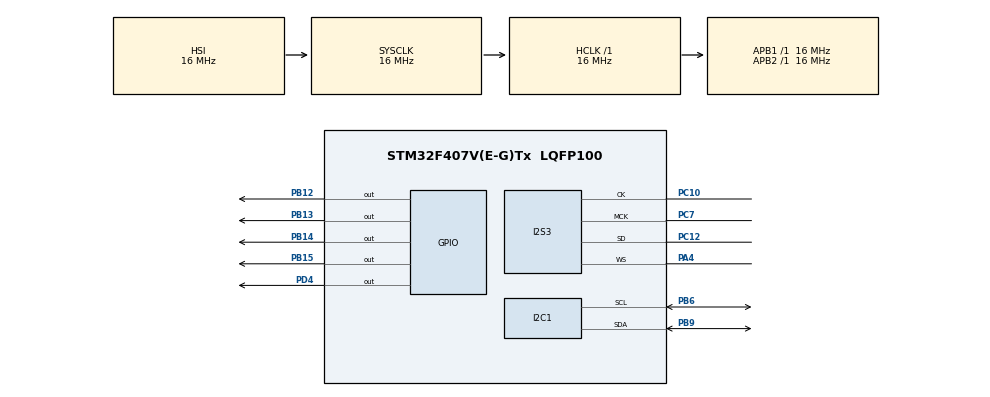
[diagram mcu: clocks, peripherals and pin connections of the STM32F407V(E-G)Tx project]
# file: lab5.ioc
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Dma.Request0=SPI3_TX
Dma.SPI3_TX.0.Direction=DMA_MEMORY_TO_PERIPH
Dma.SPI3_TX.0.FIFOMode=DMA_FIFOMODE_ENABLE
Dma.SPI3_TX.0.FIFOThreshold=DMA_FIFO_THRESHOLD_FULL
Dma.SPI3_TX.0.Instance=DMA1_Stream5
Dma.SPI3_TX.0.MemBurst=DMA_MBURST_SINGLE
Dma.SPI3_TX.0.MemDataAlignment=DMA_MDATAALIGN_HALFWORD
Dma.SPI3_TX.0.MemInc=DMA_MINC_ENABLE
Dma.SPI3_TX.0.Mode=DMA_CIRCULAR
Dma.SPI3_TX.0.PeriphBurst=DMA_PBURST_SINGLE
Dma.SPI3_TX.0.PeriphDataAlignment=DMA_PDATAALIGN_HALFWORD
Dma.SPI3_TX.0.PeriphInc=DMA_PINC_DISABLE
Dma.SPI3_TX.0.Priority=DMA_PRIORITY_LOW
I2S3.AudioFreq=I2S_AUDIOFREQ_48K
I2S3.ErrorAudioFreq=-2.34 %
I2S3.FullDuplexMode=I2S_FULLDUPLEXMODE_DISABLE
I2S3.Instance=SPI$Index
I2S3.RealAudioFreq=46.875 KHz
I2S3.VirtualMode=I2S_MODE_MASTER
Mcu.Family=STM32F4
Mcu.Name=STM32F407V(E-G)Tx
Mcu.Package=LQFP100
NVIC.DMA1_Stream5_IRQn=true\:0\:0\:false\:false\:true\:false\:true\:true
NVIC.PriorityGroup=NVIC_PRIORITYGROUP_4
PA4.Mode=Half_Duplex_Master
PA4.Signal=I2S3_WS
PB12.Signal=GPIO_Output
PB13.Signal=GPIO_Output
PB14.Signal=GPIO_Output
PB15.Signal=GPIO_Output
PB6.Mode=I2C
PB6.Signal=I2C1_SCL
PB9.Mode=I2C
PB9.Signal=I2C1_SDA
PC10.Mode=Half_Duplex_Master
PC10.Signal=I2S3_CK
PC12.Mode=Half_Duplex_Master
PC12.Signal=I2S3_SD
PC7.Mode=Master_Clock_Activated
PC7.Signal=I2S3_MCK
PD4.Signal=GPIO_Output
ProjectManager.HeapSize=0x200
ProjectManager.StackSize=0x400
ProjectManager.TargetToolchain=STM32CubeIDE
RCC.AHBFreq_Value=16000000
RCC.APB1Freq_Value=16000000
RCC.APB2Freq_Value=16000000
RCC.CortexFreq_Value=16000000
RCC.HSE_VALUE=25000000
RCC.HSI_VALUE=16000000
RCC.LSE_VALUE=32768
RCC.SYSCLKFreq_VALUE=16000000
RCC.VCOOutputFreq_Value=192000000
board=custom

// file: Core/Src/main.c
/* USER CODE BEGIN Header */
/**
  ******************************************************************************
  * @file           : main.c
  * @brief          : Main program body
  ******************************************************************************
  * @attention
  *
  * Copyright (c) 2024 STMicroelectronics.
  * All rights reserved.
  *
  * This software is licensed under terms that can be found in the LICENSE file
  * in the root directory of this software component.
  * If no LICENSE file comes with this software, it is provided AS-IS.
  *
  ******************************************************************************
  */
/* USER CODE END Header */
#include "main.h"

/* USER CODE BEGIN PTD */

typedef enum
{
	C4,
	C5,
	D5,
	E5,
	F5,
	G5,
	A5,
	B5,
	C6,
	D6,
	E6,
	F6,
	G6,
	A6,
	B6,
	C7,
	MAX_VALUE
} soundToneType;

/* USER CODE END PTD */

/* USER CODE BEGIN PD */

#define CS43L22_I2C_ADDRESS		0x94
#define I2C_TIMEOUT				10

/* USER CODE END PD */

I2C_HandleTypeDef hi2c1;

I2S_HandleTypeDef hi2s3;
DMA_HandleTypeDef hdma_spi3_tx;

/* USER CODE BEGIN PV */

int16_t dataI2S[100] = {0};

/* USER CODE END PV */

void SystemClock_Config(void);
static void MX_GPIO_Init(void);
static void MX_DMA_Init(void);
static void MX_I2C1_Init(void);
static void MX_I2S3_Init(void);

/* USER CODE BEGIN 0 */
void CS43L22_Init(void)
{
	// Enable chip
	HAL_GPIO_WritePin(GPIOD, GPIO_PIN_4, GPIO_PIN_SET);

	//
	// Initialization
	//
	uint8_t TxBuffer[2];

	TxBuffer[0] = 0x0D;
	TxBuffer[1] = 0x01;
	HAL_I2C_Master_Transmit(&hi2c1, CS43L22_I2C_ADDRESS, (uint8_t*) &TxBuffer, 2, I2C_TIMEOUT);

	TxBuffer[0] = 0x00;
	TxBuffer[1] = 0x99;
	HAL_I2C_Master_Transmit(&hi2c1, CS43L22_I2C_ADDRESS, (uint8_t*) &TxBuffer, 2, I2C_TIMEOUT);

	TxBuffer[0] = 0x47;
	TxBuffer[1] = 0x80;
	HAL_I2C_Master_Transmit(&hi2c1, CS43L22_I2C_ADDRESS, (uint8_t*) &TxBuffer, 2, I2C_TIMEOUT);

	TxBuffer[0] = 0x32;
	TxBuffer[1] = 0xFF;
	HAL_I2C_Master_Transmit(&hi2c1, CS43L22_I2C_ADDRESS, (uint8_t*) &TxBuffer, 2, I2C_TIMEOUT);

	TxBuffer[0] = 0x32;
	TxBuffer[1] = 0x7F;
	HAL_I2C_Master_Transmit(&hi2c1, CS43L22_I2C_ADDRESS, (uint8_t*) &TxBuffer, 2, I2C_TIMEOUT);

	TxBuffer[0] = 0x00;
	TxBuffer[1] = 0x00;
	HAL_I2C_Master_Transmit(&hi2c1, CS43L22_I2C_ADDRESS, (uint8_t*) &TxBuffer, 2, I2C_TIMEOUT);

	TxBuffer[0] = 0x04;
	TxBuffer[1] = 0xAF;
	HAL_I2C_Master_Transmit(&hi2c1, CS43L22_I2C_ADDRESS, (uint8_t*) &TxBuffer, 2, I2C_TIMEOUT);

	TxBuffer[0] = 0x0D;
	TxBuffer[1] = 0x70;
	HAL_I2C_Master_Transmit(&hi2c1, CS43L22_I2C_ADDRESS, (uint8_t*) &TxBuffer, 2, I2C_TIMEOUT);

	TxBuffer[0] = 0x05;
	TxBuffer[1] = 0x81;
	HAL_I2C_Master_Transmit(&hi2c1, CS43L22_I2C_ADDRESS, (uint8_t*) &TxBuffer, 2, I2C_TIMEOUT);

	TxBuffer[0] = 0x06;
	TxBuffer[1] = 0x07;
	HAL_I2C_Master_Transmit(&hi2c1, CS43L22_I2C_ADDRESS, (uint8_t*) &TxBuffer, 2, I2C_TIMEOUT);

	TxBuffer[0] = 0x0A;
	TxBuffer[1] = 0x00;
	HAL_I2C_Master_Transmit(&hi2c1, CS43L22_I2C_ADDRESS, (uint8_t*) &TxBuffer, 2, I2C_TIMEOUT);

	TxBuffer[0] = 0x27;
	TxBuffer[1] = 0x00;
	HAL_I2C_Master_Transmit(&hi2c1, CS43L22_I2C_ADDRESS, (uint8_t*) &TxBuffer, 2, I2C_TIMEOUT);

	TxBuffer[0] = 0x1A;
	TxBuffer[1] = 0x0A;
	HAL_I2C_Master_Transmit(&hi2c1, CS43L22_I2C_ADDRESS, (uint8_t*) &TxBuffer, 2, I2C_TIMEOUT);

	TxBuffer[0] = 0x1B;
	TxBuffer[1] = 0x0A;
	HAL_I2C_Master_Transmit(&hi2c1, CS43L22_I2C_ADDRESS, (uint8_t*) &TxBuffer, 2, I2C_TIMEOUT);

	TxBuffer[0] = 0x1F;
	TxBuffer[1] = 0x0F;
	HAL_I2C_Master_Transmit(&hi2c1, CS43L22_I2C_ADDRESS, (uint8_t*) &TxBuffer, 2, I2C_TIMEOUT);

	TxBuffer[0] = 0x02;
	TxBuffer[1] = 0x9E;
	HAL_I2C_Master_Transmit(&hi2c1, CS43L22_I2C_ADDRESS, (uint8_t*) &TxBuffer, 2, I2C_TIMEOUT);
}

void CS43L22_Beep(soundToneType pitch, uint32_t duration_ms)
{
	uint8_t TxBuffer[2];

	// Set volume and off time
	TxBuffer[0] = 0x1D;		// Register address
	TxBuffer[1] = 0x00;		// Value (volume and off time)
	HAL_I2C_Master_Transmit(&hi2c1, CS43L22_I2C_ADDRESS, (uint8_t*) &TxBuffer, 2, I2C_TIMEOUT);

	// Set sound frequency
	TxBuffer[0] = 0x1C;		// Register address
	switch (pitch)
	{
		case C4:
			TxBuffer[1] = 0x00;		// Value (frequency and on time)
			break;
		case C5:
			TxBuffer[1] = 0x10;
		case D5:
			TxBuffer[1] = 0x20;
		case E5:
			TxBuffer[1] = 0x30;
		case F5:
			TxBuffer[1] = 0x40;
		case G5:
			TxBuffer[1] = 0x50;
		case A5:
			TxBuffer[1] = 0x60;
		case B5:
			TxBuffer[1] = 0x70;
		case C6:
			TxBuffer[1] = 0x80;
		case D6:
			TxBuffer[1] = 0x90;
		case E6:
			TxBuffer[1] = 0xA0;
		case F6:
			TxBuffer[1] = 0xB0;
		case G6:
			TxBuffer[1] = 0xC0;
		case A6:
			TxBuffer[1] = 0xD0;
		case B6:
			TxBuffer[1] = 0xE0;
		case C7:
			TxBuffer[1] = 0xF0;
		// Assume C4 for all other cases
		case MAX_VALUE:
		default:
			TxBuffer[1] = 0x00;		// Value (frequency and on time)
			break;
	}
	HAL_I2C_Master_Transmit(&hi2c1, CS43L22_I2C_ADDRESS, (uint8_t*) &TxBuffer, 2, I2C_TIMEOUT);

	// Enable continuous mode (SOUND STARTED)
	TxBuffer[0] = 0x1E;		// Register address
	TxBuffer[1] = 0xC0;		// Value (beep and tone configuration)
	HAL_I2C_Master_Transmit(&hi2c1, CS43L22_I2C_ADDRESS, (uint8_t*) &TxBuffer, 2, I2C_TIMEOUT);

	// Playing...
	HAL_Delay(duration_ms);

	// Disable continuous mode (SOUND STOPED)
	TxBuffer[0] = 0x1E;		// Register address
	TxBuffer[1] = 0x00;		// Value (beep and tone configuration)
	HAL_I2C_Master_Transmit(&hi2c1, CS43L22_I2C_ADDRESS, (uint8_t*) &TxBuffer, 2, I2C_TIMEOUT);
}
/* USER CODE END 0 */

int main(void)
{

  /* MCU Configuration--------------------------------------------------------*/

  /* Reset of all peripherals, Initializes the Flash interface and the Systick. */
  HAL_Init();

  /* Configure the system clock */
  SystemClock_Config();

  /* Initialize all configured peripherals */
  MX_GPIO_Init();
  MX_DMA_Init();
  MX_I2C1_Init();
  MX_I2S3_Init();
  /* USER CODE BEGIN 2 */

  // Init DAC
  CS43L22_Init();

  // Transmit empty data
  HAL_I2S_Transmit_DMA(&hi2s3, (uint16_t *)dataI2S, 100);

  /* USER CODE END 2 */

  /* Infinite loop */
  /* USER CODE BEGIN WHILE */
  while (1)
  {
	  HAL_GPIO_WritePin(GPIOD, GPIO_PIN_15, GPIO_PIN_SET);
	  CS43L22_Beep(C5, 100);
	  HAL_GPIO_WritePin(GPIOD, GPIO_PIN_15, GPIO_PIN_RESET);
	  HAL_Delay(100);

	  HAL_GPIO_WritePin(GPIOD, GPIO_PIN_14, GPIO_PIN_SET);
	  CS43L22_Beep(E5, 100);
	  HAL_GPIO_WritePin(GPIOD, GPIO_PIN_14, GPIO_PIN_RESET);
	  HAL_Delay(100);

	  HAL_GPIO_WritePin(GPIOD, GPIO_PIN_13, GPIO_PIN_SET);
	  CS43L22_Beep(F5, 100);
	  HAL_GPIO_WritePin(GPIOD, GPIO_PIN_13, GPIO_PIN_RESET);
	  HAL_Delay(100);

	  HAL_GPIO_WritePin(GPIOD, GPIO_PIN_12, GPIO_PIN_SET);
	  CS43L22_Beep(G5, 100);
	  HAL_GPIO_WritePin(GPIOD, GPIO_PIN_12, GPIO_PIN_RESET);
	  HAL_Delay(100);

	  HAL_GPIO_WritePin(GPIOD, GPIO_PIN_15, GPIO_PIN_SET);
	  CS43L22_Beep(G5, 100);
	  HAL_GPIO_WritePin(GPIOD, GPIO_PIN_15, GPIO_PIN_RESET);
	  HAL_Delay(500);

	  HAL_GPIO_WritePin(GPIOD, GPIO_PIN_14, GPIO_PIN_SET);
	  CS43L22_Beep(A5, 100);
	  HAL_GPIO_WritePin(GPIOD, GPIO_PIN_14, GPIO_PIN_RESET);
	  HAL_Delay(500);

	  HAL_GPIO_WritePin(GPIOD, GPIO_PIN_13, GPIO_PIN_SET);
	  CS43L22_Beep(G5, 100);
	  HAL_GPIO_WritePin(GPIOD, GPIO_PIN_13, GPIO_PIN_RESET);
	  HAL_Delay(100);

	  HAL_GPIO_WritePin(GPIOD, GPIO_PIN_12, GPIO_PIN_SET);
	  CS43L22_Beep(F5, 100);
	  HAL_GPIO_WritePin(GPIOD, GPIO_PIN_12, GPIO_PIN_RESET);
	  HAL_Delay(100);

	  HAL_GPIO_WritePin(GPIOD, GPIO_PIN_15, GPIO_PIN_SET);
	  CS43L22_Beep(E5, 100);
	  HAL_GPIO_WritePin(GPIOD, GPIO_PIN_15, GPIO_PIN_RESET);
	  HAL_Delay(100);

	  HAL_GPIO_WritePin(GPIOD, GPIO_PIN_14, GPIO_PIN_SET);
	  CS43L22_Beep(A5, 100);
	  HAL_GPIO_WritePin(GPIOD, GPIO_PIN_14, GPIO_PIN_RESET);
	  HAL_Delay(100);

    /* USER CODE END WHILE */

  }
}

void SystemClock_Config(void)
{
  RCC_OscInitTypeDef RCC_OscInitStruct = {0};
  RCC_ClkInitTypeDef RCC_ClkInitStruct = {0};

  /** Macro to configure the PLL multiplication factor
  */
  __HAL_RCC_PLL_PLLM_CONFIG(16);

  /** Macro to configure the PLL clock source
  */
  __HAL_RCC_PLL_PLLSOURCE_CONFIG(RCC_PLLSOURCE_HSI);

  /** Configure the main internal regulator output voltage
  */
  __HAL_RCC_PWR_CLK_ENABLE();
  __HAL_PWR_VOLTAGESCALING_CONFIG(PWR_REGULATOR_VOLTAGE_SCALE1);

  /** Initializes the RCC Oscillators according to the specified parameters
  * in the RCC_OscInitTypeDef structure.
  */
  RCC_OscInitStruct.OscillatorType = RCC_OSCILLATORTYPE_HSI;
  RCC_OscInitStruct.HSIState = RCC_HSI_ON;
  RCC_OscInitStruct.HSICalibrationValue = RCC_HSICALIBRATION_DEFAULT;
  RCC_OscInitStruct.PLL.PLLState = RCC_PLL_NONE;
  RCC_OscInitStruct.PLL.PLLSource = RCC_PLLSOURCE_HSI;
  if (HAL_RCC_OscConfig(&RCC_OscInitStruct) != HAL_OK)
  {
    Error_Handler();
  }

  /** Initializes the CPU, AHB and APB buses clocks
  */
  RCC_ClkInitStruct.ClockType = RCC_CLOCKTYPE_HCLK|RCC_CLOCKTYPE_SYSCLK
                              |RCC_CLOCKTYPE_PCLK1|RCC_CLOCKTYPE_PCLK2;
  RCC_ClkInitStruct.SYSCLKSource = RCC_SYSCLKSOURCE_HSI;
  RCC_ClkInitStruct.AHBCLKDivider = RCC_SYSCLK_DIV1;
  RCC_ClkInitStruct.APB1CLKDivider = RCC_HCLK_DIV1;
  RCC_ClkInitStruct.APB2CLKDivider = RCC_HCLK_DIV1;

  if (HAL_RCC_ClockConfig(&RCC_ClkInitStruct, FLASH_LATENCY_0) != HAL_OK)
  {
    Error_Handler();
  }
}

static void MX_I2C1_Init(void)
{

  hi2c1.Instance = I2C1;
  hi2c1.Init.ClockSpeed = 100000;
  hi2c1.Init.DutyCycle = I2C_DUTYCYCLE_2;
  hi2c1.Init.OwnAddress1 = 0;
  hi2c1.Init.AddressingMode = I2C_ADDRESSINGMODE_7BIT;
  hi2c1.Init.DualAddressMode = I2C_DUALADDRESS_DISABLE;
  hi2c1.Init.OwnAddress2 = 0;
  hi2c1.Init.GeneralCallMode = I2C_GENERALCALL_DISABLE;
  hi2c1.Init.NoStretchMode = I2C_NOSTRETCH_DISABLE;
  if (HAL_I2C_Init(&hi2c1) != HAL_OK)
  {
    Error_Handler();
  }

}

static void MX_I2S3_Init(void)
{

  hi2s3.Instance = SPI3;
  hi2s3.Init.Mode = I2S_MODE_MASTER_TX;
  hi2s3.Init.Standard = I2S_STANDARD_PHILIPS;
  hi2s3.Init.DataFormat = I2S_DATAFORMAT_16B;
  hi2s3.Init.MCLKOutput = I2S_MCLKOUTPUT_ENABLE;
  hi2s3.Init.AudioFreq = I2S_AUDIOFREQ_48K;
  hi2s3.Init.CPOL = I2S_CPOL_LOW;
  hi2s3.Init.ClockSource = I2S_CLOCK_PLL;
  hi2s3.Init.FullDuplexMode = I2S_FULLDUPLEXMODE_DISABLE;
  if (HAL_I2S_Init(&hi2s3) != HAL_OK)
  {
    Error_Handler();
  }

}

static void MX_DMA_Init(void)
{

  /* DMA controller clock enable */
  __HAL_RCC_DMA1_CLK_ENABLE();

  /* DMA interrupt init */
  /* DMA1_Stream5_IRQn interrupt configuration */
  HAL_NVIC_SetPriority(DMA1_Stream5_IRQn, 0, 0);
  HAL_NVIC_EnableIRQ(DMA1_Stream5_IRQn);

}

static void MX_GPIO_Init(void)
{
  GPIO_InitTypeDef GPIO_InitStruct = {0};

  /* GPIO Ports Clock Enable */
  __HAL_RCC_GPIOA_CLK_ENABLE();
  __HAL_RCC_GPIOD_CLK_ENABLE();
  __HAL_RCC_GPIOC_CLK_ENABLE();
  __HAL_RCC_GPIOB_CLK_ENABLE();

  /*Configure GPIO pin Output Level */
  HAL_GPIO_WritePin(GPIOD, GPIO_PIN_12|GPIO_PIN_13|GPIO_PIN_14|GPIO_PIN_15
                          |GPIO_PIN_4, GPIO_PIN_RESET);

  /*Configure GPIO pins : PD12 PD13 PD14 PD15
                           PD4 */
  GPIO_InitStruct.Pin = GPIO_PIN_12|GPIO_PIN_13|GPIO_PIN_14|GPIO_PIN_15
                          |GPIO_PIN_4;
  GPIO_InitStruct.Mode = GPIO_MODE_OUTPUT_PP;
  GPIO_InitStruct.Pull = GPIO_NOPULL;
  GPIO_InitStruct.Speed = GPIO_SPEED_FREQ_LOW;
  HAL_GPIO_Init(GPIOD, &GPIO_InitStruct);

}

void Error_Handler(void)
{
  __disable_irq();
  while (1)
  {
  }
}
